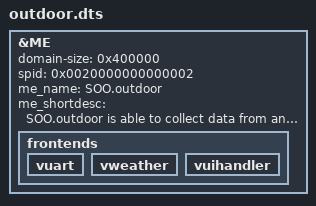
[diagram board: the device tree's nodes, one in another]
/*
 * Copyright (C) 2016-2018 Daniel Rossier <daniel.rossier@soo.tech>
 *
 * This program is free software; you can redistribute it and/or modify
 * it under the terms of the GNU General Public License version 2 as
 * published by the Free Software Foundation.
 *
 * This program is distributed in the hope that it will be useful,
 * but WITHOUT ANY WARRANTY; without even the implied warranty of
 * MERCHANTABILITY or FITNESS FOR A PARTICULAR PURPOSE.  See the
 * GNU General Public License for more details.
 *
 * You should have received a copy of the GNU General Public License
 * along with this program; if not, write to the Free Software
 * Foundation, Inc., 51 Franklin St, Fifth Floor, Boston, MA  02110-1301  USA
 *
 */

/dts-v1/;

#include "soo.dtsi"

&ME {
	/* 4 MB is enough */
	domain-size = <0x400000>;
	
	/* SPID on 64-bit encoding */
	spid = /bits/ 64 <0x0020000000000002>;
		
	/* Name of this ME */
	me_name = "SOO.outdoor";
		
	/* Short description */
	me_shortdesc =
			
"SOO.outdoor is able to collect data from any weather station. This ME \
can be used in conjunction with other MEs which can use this kind of data.";

	frontends {
		/* Enabling the console */
		vuart {
			status = "ok";
		};
	
		vweather {
			status = "ok";
		};
	  
		vuihandler {
			status = "ok";
		};
	};
};
	
